VERSION 5.7 ;
  NOWIREEXTENSIONATPIN ON ;
  DIVIDERCHAR "/" ;
  BUSBITCHARS "[]" ;
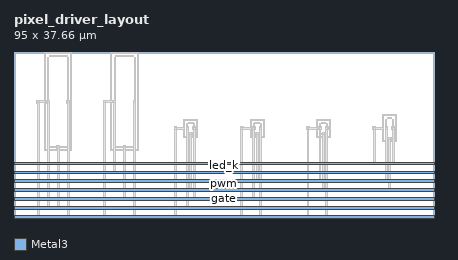
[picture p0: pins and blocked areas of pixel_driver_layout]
MACRO pixel_driver_layout
  CLASS BLOCK ;
  FOREIGN pixel_driver_layout ;
  ORIGIN 0.000 0.300 ;
  SIZE 95.000 BY 37.660 ;
  PIN VSS
    DIRECTION INOUT ;
    USE GROUND ;
    PORT
      LAYER Metal3 ;
        RECT 0.000 -0.300 95.000 0.300 ;
    END
  END VSS
  PIN bias
    DIRECTION INOUT ;
    USE SIGNAL ;
    ANTENNAGATEAREA 80.000000 ;
    ANTENNADIFFAREA 9.679999 ;
    PORT
      LAYER Metal3 ;
        RECT 0.000 1.700 95.000 2.300 ;
    END
  END bias
  PIN gate
    DIRECTION OUTPUT ;
    USE SIGNAL ;
    ANTENNAGATEAREA 80.000000 ;
    ANTENNADIFFAREA 1.760000 ;
    PORT
      LAYER Metal3 ;
        RECT 0.000 3.700 95.000 4.300 ;
    END
  END gate
  PIN pwm
    DIRECTION INPUT ;
    USE SIGNAL ;
    ANTENNAGATEAREA 8.000000 ;
    PORT
      LAYER Metal3 ;
        RECT 0.000 5.700 95.000 6.300 ;
    END
  END pwm
  PIN pwm_b
    DIRECTION OUTPUT ;
    USE SIGNAL ;
    ANTENNAGATEAREA 2.000000 ;
    ANTENNADIFFAREA 2.640000 ;
    PORT
      LAYER Metal3 ;
        RECT 0.000 7.700 95.000 8.300 ;
    END
  END pwm_b
  PIN led_k
    DIRECTION INOUT ;
    USE SIGNAL ;
    ANTENNADIFFAREA 8.800000 ;
    PORT
      LAYER Metal3 ;
        RECT 0.000 9.700 95.000 10.300 ;
    END
  END led_k
  PIN vlogic
    DIRECTION INOUT ;
    USE POWER ;
    PORT
      LAYER Metal3 ;
        RECT 0.000 11.700 95.000 12.300 ;
    END
  END vlogic
  OBS
      LAYER Metal1 ;
        RECT 6.905 36.825 13.095 37.055 ;
        RECT 5.200 26.250 5.800 26.300 ;
        RECT 6.905 26.250 7.135 36.825 ;
        RECT 8.010 36.165 11.990 36.395 ;
        RECT 7.625 26.300 7.855 35.990 ;
        RECT 12.145 26.300 12.375 35.990 ;
        RECT 5.200 25.750 7.170 26.250 ;
        RECT 5.200 25.700 5.800 25.750 ;
        RECT 6.905 15.175 7.135 25.750 ;
        RECT 7.440 25.700 8.040 26.300 ;
        RECT 11.960 25.700 12.560 26.300 ;
        RECT 7.625 16.010 7.855 25.700 ;
        RECT 9.700 15.835 10.300 16.020 ;
        RECT 12.145 16.010 12.375 25.700 ;
        RECT 8.010 15.605 11.990 15.835 ;
        RECT 9.700 15.420 10.300 15.605 ;
        RECT 12.865 15.175 13.095 36.825 ;
        RECT 21.905 36.825 28.095 37.055 ;
        RECT 20.200 26.250 20.800 26.300 ;
        RECT 21.905 26.250 22.135 36.825 ;
        RECT 23.010 36.165 26.990 36.395 ;
        RECT 22.625 26.300 22.855 35.990 ;
        RECT 27.145 26.300 27.375 35.990 ;
        RECT 20.200 25.750 22.170 26.250 ;
        RECT 20.200 25.700 20.800 25.750 ;
        RECT 6.905 14.945 13.095 15.175 ;
        RECT 21.905 15.175 22.135 25.750 ;
        RECT 22.440 25.700 23.040 26.300 ;
        RECT 26.960 25.700 27.560 26.300 ;
        RECT 22.625 16.010 22.855 25.700 ;
        RECT 24.700 15.835 25.300 16.020 ;
        RECT 27.145 16.010 27.375 25.700 ;
        RECT 23.010 15.605 26.990 15.835 ;
        RECT 24.700 15.420 25.300 15.605 ;
        RECT 27.865 15.175 28.095 36.825 ;
        RECT 83.405 22.825 86.595 23.055 ;
        RECT 38.405 21.825 41.595 22.055 ;
        RECT 36.200 20.250 36.800 20.300 ;
        RECT 38.405 20.250 38.635 21.825 ;
        RECT 39.510 21.165 40.490 21.395 ;
        RECT 39.125 20.300 39.355 20.990 ;
        RECT 40.645 20.300 40.875 20.990 ;
        RECT 36.200 19.750 38.670 20.250 ;
        RECT 36.200 19.700 36.800 19.750 ;
        RECT 38.405 18.175 38.635 19.750 ;
        RECT 38.940 19.700 39.540 20.300 ;
        RECT 40.460 19.700 41.060 20.300 ;
        RECT 39.125 19.010 39.355 19.700 ;
        RECT 39.700 18.835 40.300 19.020 ;
        RECT 40.645 19.010 40.875 19.700 ;
        RECT 39.510 18.605 40.490 18.835 ;
        RECT 39.700 18.420 40.300 18.605 ;
        RECT 41.365 18.175 41.595 21.825 ;
        RECT 53.405 21.825 56.595 22.055 ;
        RECT 51.200 20.250 51.800 20.300 ;
        RECT 53.405 20.250 53.635 21.825 ;
        RECT 54.510 21.165 55.490 21.395 ;
        RECT 54.125 20.300 54.355 20.990 ;
        RECT 55.645 20.300 55.875 20.990 ;
        RECT 51.200 19.750 53.670 20.250 ;
        RECT 51.200 19.700 51.800 19.750 ;
        RECT 38.405 17.945 41.595 18.175 ;
        RECT 53.405 18.175 53.635 19.750 ;
        RECT 53.940 19.700 54.540 20.300 ;
        RECT 55.460 19.700 56.060 20.300 ;
        RECT 54.125 19.010 54.355 19.700 ;
        RECT 54.700 18.835 55.300 19.020 ;
        RECT 55.645 19.010 55.875 19.700 ;
        RECT 54.510 18.605 55.490 18.835 ;
        RECT 54.700 18.420 55.300 18.605 ;
        RECT 56.365 18.175 56.595 21.825 ;
        RECT 68.405 21.825 71.595 22.055 ;
        RECT 66.200 20.250 66.800 20.300 ;
        RECT 68.405 20.250 68.635 21.825 ;
        RECT 69.510 21.165 70.490 21.395 ;
        RECT 69.125 20.300 69.355 20.990 ;
        RECT 70.645 20.300 70.875 20.990 ;
        RECT 66.200 19.750 68.670 20.250 ;
        RECT 66.200 19.700 66.800 19.750 ;
        RECT 53.405 17.945 56.595 18.175 ;
        RECT 68.405 18.175 68.635 19.750 ;
        RECT 68.940 19.700 69.540 20.300 ;
        RECT 70.460 19.700 71.060 20.300 ;
        RECT 69.125 19.010 69.355 19.700 ;
        RECT 69.700 18.835 70.300 19.020 ;
        RECT 70.645 19.010 70.875 19.700 ;
        RECT 69.510 18.605 70.490 18.835 ;
        RECT 69.700 18.420 70.300 18.605 ;
        RECT 71.365 18.175 71.595 21.825 ;
        RECT 81.200 20.250 81.800 20.300 ;
        RECT 83.405 20.250 83.635 22.825 ;
        RECT 84.510 22.165 85.490 22.395 ;
        RECT 84.125 20.300 84.355 21.990 ;
        RECT 85.645 20.300 85.875 21.990 ;
        RECT 81.200 19.750 83.670 20.250 ;
        RECT 81.200 19.700 81.800 19.750 ;
        RECT 68.405 17.945 71.595 18.175 ;
        RECT 83.405 17.175 83.635 19.750 ;
        RECT 83.940 19.700 84.540 20.300 ;
        RECT 85.460 19.700 86.060 20.300 ;
        RECT 84.125 18.010 84.355 19.700 ;
        RECT 84.700 17.835 85.300 18.020 ;
        RECT 85.645 18.010 85.875 19.700 ;
        RECT 84.510 17.605 85.490 17.835 ;
        RECT 84.700 17.420 85.300 17.605 ;
        RECT 86.365 17.175 86.595 22.825 ;
        RECT 83.405 16.945 86.595 17.175 ;
        RECT 21.905 14.945 28.095 15.175 ;
      LAYER Via1 ;
        RECT 5.370 25.870 5.630 26.130 ;
        RECT 7.610 25.870 7.870 26.130 ;
        RECT 12.130 25.870 12.390 26.130 ;
        RECT 9.870 15.590 10.130 15.850 ;
        RECT 20.370 25.870 20.630 26.130 ;
        RECT 22.610 25.870 22.870 26.130 ;
        RECT 27.130 25.870 27.390 26.130 ;
        RECT 24.870 15.590 25.130 15.850 ;
        RECT 36.370 19.870 36.630 20.130 ;
        RECT 39.110 19.870 39.370 20.130 ;
        RECT 40.630 19.870 40.890 20.130 ;
        RECT 39.870 18.590 40.130 18.850 ;
        RECT 51.370 19.870 51.630 20.130 ;
        RECT 54.110 19.870 54.370 20.130 ;
        RECT 55.630 19.870 55.890 20.130 ;
        RECT 54.870 18.590 55.130 18.850 ;
        RECT 66.370 19.870 66.630 20.130 ;
        RECT 69.110 19.870 69.370 20.130 ;
        RECT 70.630 19.870 70.890 20.130 ;
        RECT 69.870 18.590 70.130 18.850 ;
        RECT 81.370 19.870 81.630 20.130 ;
        RECT 84.110 19.870 84.370 20.130 ;
        RECT 85.630 19.870 85.890 20.130 ;
        RECT 84.870 17.590 85.130 17.850 ;
      LAYER Metal2 ;
        RECT 5.280 25.780 5.720 26.220 ;
        RECT 7.520 25.780 7.960 26.220 ;
        RECT 12.040 25.780 12.480 26.220 ;
        RECT 20.280 25.780 20.720 26.220 ;
        RECT 22.520 25.780 22.960 26.220 ;
        RECT 27.040 25.780 27.480 26.220 ;
        RECT 5.300 0.220 5.700 25.780 ;
        RECT 7.540 2.220 7.940 25.780 ;
        RECT 9.780 15.500 10.220 15.940 ;
        RECT 9.800 2.220 10.200 15.500 ;
        RECT 7.520 1.780 7.960 2.220 ;
        RECT 9.780 1.780 10.220 2.220 ;
        RECT 12.060 0.220 12.460 25.780 ;
        RECT 20.300 0.220 20.700 25.780 ;
        RECT 22.540 10.220 22.940 25.780 ;
        RECT 24.780 15.500 25.220 15.940 ;
        RECT 22.520 9.780 22.960 10.220 ;
        RECT 24.800 4.220 25.200 15.500 ;
        RECT 24.780 3.780 25.220 4.220 ;
        RECT 27.060 0.220 27.460 25.780 ;
        RECT 36.280 19.780 36.720 20.220 ;
        RECT 39.020 19.780 39.460 20.220 ;
        RECT 40.540 19.780 40.980 20.220 ;
        RECT 51.280 19.780 51.720 20.220 ;
        RECT 54.020 19.780 54.460 20.220 ;
        RECT 55.540 19.780 55.980 20.220 ;
        RECT 66.280 19.780 66.720 20.220 ;
        RECT 69.020 19.780 69.460 20.220 ;
        RECT 70.540 19.780 70.980 20.220 ;
        RECT 81.280 19.780 81.720 20.220 ;
        RECT 84.020 19.780 84.460 20.220 ;
        RECT 85.540 19.780 85.980 20.220 ;
        RECT 36.300 0.220 36.700 19.780 ;
        RECT 39.040 2.220 39.440 19.780 ;
        RECT 39.780 18.500 40.220 18.940 ;
        RECT 39.800 6.220 40.200 18.500 ;
        RECT 39.780 5.780 40.220 6.220 ;
        RECT 40.560 4.220 40.960 19.780 ;
        RECT 40.540 3.780 40.980 4.220 ;
        RECT 39.020 1.780 39.460 2.220 ;
        RECT 51.300 0.220 51.700 19.780 ;
        RECT 54.040 4.220 54.440 19.780 ;
        RECT 54.780 18.500 55.220 18.940 ;
        RECT 54.800 8.220 55.200 18.500 ;
        RECT 54.780 7.780 55.220 8.220 ;
        RECT 54.020 3.780 54.460 4.220 ;
        RECT 55.560 0.220 55.960 19.780 ;
        RECT 66.300 0.220 66.700 19.780 ;
        RECT 69.040 8.220 69.440 19.780 ;
        RECT 69.780 18.500 70.220 18.940 ;
        RECT 69.020 7.780 69.460 8.220 ;
        RECT 69.800 6.220 70.200 18.500 ;
        RECT 69.780 5.780 70.220 6.220 ;
        RECT 70.560 0.220 70.960 19.780 ;
        RECT 81.300 12.220 81.700 19.780 ;
        RECT 81.280 11.780 81.720 12.220 ;
        RECT 84.040 8.220 84.440 19.780 ;
        RECT 84.780 17.500 85.220 17.940 ;
        RECT 84.020 7.780 84.460 8.220 ;
        RECT 84.800 6.220 85.200 17.500 ;
        RECT 85.560 12.220 85.960 19.780 ;
        RECT 85.540 11.780 85.980 12.220 ;
        RECT 84.780 5.780 85.220 6.220 ;
        RECT 5.280 -0.220 5.720 0.220 ;
        RECT 12.040 -0.220 12.480 0.220 ;
        RECT 20.280 -0.220 20.720 0.220 ;
        RECT 27.040 -0.220 27.480 0.220 ;
        RECT 36.280 -0.220 36.720 0.220 ;
        RECT 51.280 -0.220 51.720 0.220 ;
        RECT 55.540 -0.220 55.980 0.220 ;
        RECT 66.280 -0.220 66.720 0.220 ;
        RECT 70.540 -0.220 70.980 0.220 ;
      LAYER Via2 ;
        RECT 7.600 1.860 7.880 2.140 ;
        RECT 9.860 1.860 10.140 2.140 ;
        RECT 22.600 9.860 22.880 10.140 ;
        RECT 24.860 3.860 25.140 4.140 ;
        RECT 39.860 5.860 40.140 6.140 ;
        RECT 40.620 3.860 40.900 4.140 ;
        RECT 39.100 1.860 39.380 2.140 ;
        RECT 54.860 7.860 55.140 8.140 ;
        RECT 54.100 3.860 54.380 4.140 ;
        RECT 69.100 7.860 69.380 8.140 ;
        RECT 69.860 5.860 70.140 6.140 ;
        RECT 81.360 11.860 81.640 12.140 ;
        RECT 84.100 7.860 84.380 8.140 ;
        RECT 85.620 11.860 85.900 12.140 ;
        RECT 84.860 5.860 85.140 6.140 ;
        RECT 5.360 -0.140 5.640 0.140 ;
        RECT 12.120 -0.140 12.400 0.140 ;
        RECT 20.360 -0.140 20.640 0.140 ;
        RECT 27.120 -0.140 27.400 0.140 ;
        RECT 36.360 -0.140 36.640 0.140 ;
        RECT 51.360 -0.140 51.640 0.140 ;
        RECT 55.620 -0.140 55.900 0.140 ;
        RECT 66.360 -0.140 66.640 0.140 ;
        RECT 70.620 -0.140 70.900 0.140 ;
  END
END pixel_driver_layout
END LIBRARY

